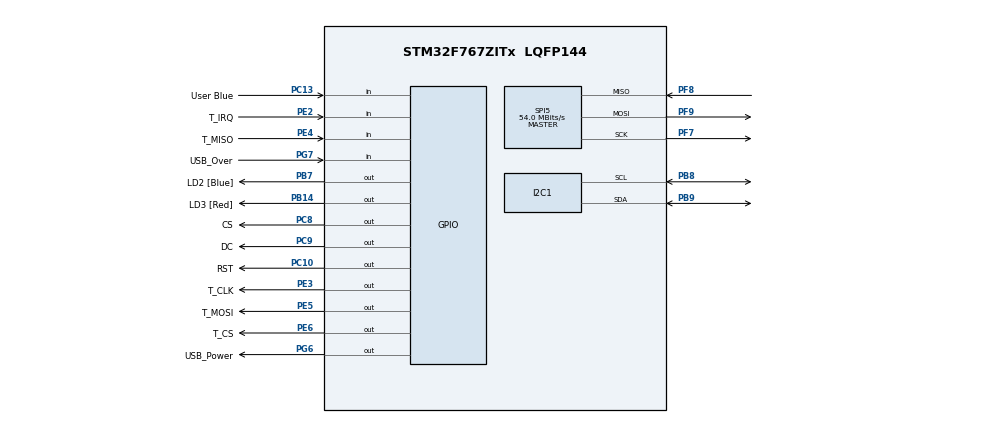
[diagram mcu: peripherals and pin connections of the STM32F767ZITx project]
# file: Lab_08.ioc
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CORTEX_M7.ART_ACCELERATOR_ENABLE=1
CORTEX_M7.CPU_DCache=Enabled
CORTEX_M7.CPU_ICache=Enabled
CORTEX_M7.MPU_Control=__NULL
CORTEX_M7.PREFETCH_ENABLE=1
I2C1.Timing=0x20404768
Mcu.Family=STM32F7
Mcu.Name=STM32F767ZITx
Mcu.Package=LQFP144
NVIC.PriorityGroup=NVIC_PRIORITYGROUP_4
PB14.GPIO_Label=LD3 [Red]
PB14.Signal=GPIO_Output
PB7.GPIO_Label=LD2 [Blue]
PB7.Signal=GPIO_Output
PB8.Mode=I2C
PB8.Signal=I2C1_SCL
PB9.Mode=I2C
PB9.Signal=I2C1_SDA
PC10.GPIO_Label=RST
PC10.GPIO_Speed=GPIO_SPEED_FREQ_VERY_HIGH
PC10.Signal=GPIO_Output
PC13.GPIO_Label=User Blue
PC13.Signal=GPIO_Input
PC8.GPIO_Label=CS
PC8.GPIO_Speed=GPIO_SPEED_FREQ_VERY_HIGH
PC8.Signal=GPIO_Output
PC9.GPIO_Label=DC
PC9.GPIO_Speed=GPIO_SPEED_FREQ_VERY_HIGH
PC9.Signal=GPIO_Output
PE2.GPIO_Label=T_IRQ
PE2.Signal=GPIO_Input
PE3.GPIO_Label=T_CLK
PE3.GPIO_Speed=GPIO_SPEED_FREQ_VERY_HIGH
PE3.Signal=GPIO_Output
PE4.GPIO_Label=T_MISO
PE4.Signal=GPIO_Input
PE5.GPIO_Label=T_MOSI
PE5.GPIO_Speed=GPIO_SPEED_FREQ_VERY_HIGH
PE5.Signal=GPIO_Output
PE6.GPIO_Label=T_CS
PE6.GPIO_Speed=GPIO_SPEED_FREQ_VERY_HIGH
PE6.Signal=GPIO_Output
PF7.Mode=Full_Duplex_Master
PF7.Signal=SPI5_SCK
PF8.Mode=Full_Duplex_Master
PF8.Signal=SPI5_MISO
PF9.Mode=Full_Duplex_Master
PF9.Signal=SPI5_MOSI
PG6.GPIO_Label=USB_Power
PG6.Signal=GPIO_Output
PG7.GPIO_Label=USB_Over
PG7.Signal=GPIO_Input
ProjectManager.HeapSize=0x200
ProjectManager.StackSize=0x400
ProjectManager.TargetToolchain=STM32CubeIDE
RCC.AHBFreq_Value=216000000
RCC.APB1CLKDivider=RCC_HCLK_DIV4
RCC.APB1Freq_Value=54000000
RCC.APB1TimFreq_Value=108000000
RCC.APB2CLKDivider=RCC_HCLK_DIV2
RCC.APB2Freq_Value=108000000
RCC.APB2TimFreq_Value=216000000
RCC.CortexFreq_Value=216000000
RCC.HCLKFreq_Value=216000000
RCC.HSE_VALUE=25000000
RCC.HSI_VALUE=16000000
RCC.LSE_VALUE=32768
RCC.PLLM=8
RCC.PLLN=216
RCC.PLLQ=9
RCC.SYSCLKFreq_VALUE=216000000
RCC.SYSCLKSource=RCC_SYSCLKSOURCE_PLLCLK
RCC.USBFreq_Value=48000000
RCC.VCOOutputFreq_Value=432000000
SPI5.CalculateBaudRate=54.0 MBits/s
SPI5.DataSize=SPI_DATASIZE_8BIT
SPI5.Direction=SPI_DIRECTION_2LINES
SPI5.Mode=SPI_MODE_MASTER
SPI5.NSSPMode=SPI_NSS_PULSE_DISABLE
SPI5.VirtualType=VM_MASTER
TIM1.ClockDivision=TIM_CLOCKDIVISION_DIV2
TIM1.Period=0
TIM1.Prescaler=10000
VP_RNG_VS_RNG.Mode=RNG_Activate
VP_TIM1_VS_ClockSourceINT.Mode=Internal
board=custom

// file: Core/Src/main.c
/* USER CODE BEGIN Header */
/**
  ******************************************************************************
  * @file           : main.c
  * @brief          : Main program body
  ******************************************************************************
  * @attention
  *
  * Copyright (c) 2023 STMicroelectronics.
  * All rights reserved.
  *
  * This software is licensed under terms that can be found in the LICENSE file
  * in the root directory of this software component.
  * If no LICENSE file comes with this software, it is provided AS-IS.
  *
  ******************************************************************************
  */
/* USER CODE END Header */
#include "main.h"
#include "i2c.h"
#include "rng.h"
#include "spi.h"
#include "tim.h"
#include "gpio.h"

/* USER CODE BEGIN Includes */

#include "ILI9341_GFX.h"
#include "ILI9341_STM32_Driver.h"
#include "ILI9341_Touchscreen.h"
#include "string.h"
#include "stdio.h"
#include "picture.h"
/* USER CODE END Includes */

/* USER CODE BEGIN PV */

u_int16_t rcolor ;
u_int16_t gcolor ;
u_int16_t bcolor ;
u_int16_t rgbcolor;

float h=30.0,t=40.0;
u_int8_t step =0;
HAL_StatusTypeDef status;

/* USER CODE END PV */

void SystemClock_Config(void);
/* USER CODE BEGIN PFP */

uint16_t CRC16_2(uint8_t *,uint8_t);
/* USER CODE END PFP */

int main(void)
{
  /* USER CODE BEGIN 1 */
  char str[50];
  uint8_t cmdBuffer[3];
  uint8_t dataBuffer[8];
  /* USER CODE END 1 */

  /* Enable I-Cache---------------------------------------------------------*/
  SCB_EnableICache();

  /* Enable D-Cache---------------------------------------------------------*/
  SCB_EnableDCache();

  /* MCU Configuration--------------------------------------------------------*/

  /* Reset of all peripherals, Initializes the Flash interface and the Systick. */
  HAL_Init();

  /* Configure the system clock */
  SystemClock_Config();

  /* Initialize all configured peripherals */
  MX_GPIO_Init();
  MX_RNG_Init();
  MX_SPI5_Init();
  MX_TIM1_Init();
  MX_I2C1_Init();
  /* USER CODE BEGIN 2 */
  ILI9341_Init();

  ILI9341_Set_Rotation(SCREEN_HORIZONTAL_2);

  ILI9341_Fill_Screen(WHITE);
  uint16_t red=0;
  uint16_t green=0;
  uint16_t blue=0;
  uint16_t timeout=0;
  cmdBuffer[0]=0x03;
  cmdBuffer[1]=0x00;
  cmdBuffer[2]=0x04;

  /* USER CODE END 2 */

  /* Infinite loop */
  /* USER CODE BEGIN WHILE */
  while (1)
  {
    /* USER CODE END WHILE
     * #define ILI9341_SCREEN_HEIGHT 240
		#define ILI9341_SCREEN_WIDTH 	320
     *  */

	  HAL_Delay(50);

	  HAL_I2C_Master_Transmit(&hi2c1, 0x5c<<1, cmdBuffer, 3, 200);
	  HAL_I2C_Master_Transmit(&hi2c1, 0x5c<<1, cmdBuffer, 3, 200);
	  HAL_Delay(1);
	  HAL_I2C_Master_Receive(&hi2c1, 0x5c<<1, dataBuffer, 8, 200);
	  uint16_t Rcrc = dataBuffer[7]<<8;
	  Rcrc +=dataBuffer[6];
	  if (Rcrc == CRC16_2(dataBuffer,6))
	  {
		  uint16_t temperature = ((dataBuffer[4]%0x7F)<<8)+dataBuffer[5];
		  t = temperature/10.0;
		  t=(((dataBuffer[4]&0x80)>>7)==1)?(t*(-1)):t;
		  uint16_t humidity=(dataBuffer[2]<<8)+dataBuffer[3];
		  h= humidity/10.0;

	  }
	  char temperature[4];
	  char Humudity[10];

	  sprintf(temperature,"%4.1fC",t);
	  ILI9341_Draw_Text(temperature, 20, 25, BLACK, 2, WHITE);

	  sprintf(Humudity,"%4.1f%%RH",h);
	  ILI9341_Draw_Text(Humudity, 180, 25, BLACK, 2, WHITE);

	  rcolor=((red*25+5)>>3)<<11;
	  gcolor=((green*25+5)>>2)<<5;
	  bcolor=(blue*25+5)>>3;
	  rgbcolor=rcolor|gcolor|bcolor;

	  if(TP_Touchpad_Pressed())
	  {
		  uint16_t x_pos=0;
		  uint16_t y_pos=0;
		  HAL_GPIO_WritePin(GPIOB, LD3_Pin|LD2_Pin, GPIO_PIN_SET);
		  uint16_t position_array[2];
		  if(TP_Read_Coordinates(position_array)==TOUCHPAD_DATA_OK)
		  {
			  x_pos= position_array[0];
			  y_pos=position_array[1];
			  if(x_pos>100 && x_pos<125&&y_pos>285&&y_pos<305)
			  {
				  red++;
			  	  if (red>10)
			  	  {

			  		  red=0;
			  	  }
			  }
			  if(x_pos>150 && x_pos<180&&y_pos>285&&y_pos<305)
			  {

				  green++;
			  	  if (green>10)
			  	  {
			  		green=0;
			  	  }
			  }
			  if(x_pos>200 && x_pos<230&&y_pos>285&&y_pos<305)
			  {

				  blue++;
				  if (blue>10)
				  {
					  blue=0;
				  }
			  }
			  if(x_pos>30 && x_pos<50&&y_pos>180&&y_pos<220)
			  {

			  	  ILI9341_Fill_Screen(WHITE);
			  	  ILI9341_Draw_Image((const char*)picture, SCREEN_HORIZONTAL_2);
			  	  ILI9341_Draw_Text("Group No18", 145, 45, rgbcolor, 2, WHITE);
			  	  ILI9341_Draw_Text("Jaruphat", 145, 65, rgbcolor, 2, WHITE);
			  	  ILI9341_Draw_Text("Khenprom", 145, 85, rgbcolor, 2, WHITE);
			  	  ILI9341_Draw_Text("64015019", 145, 105, rgbcolor, 2, WHITE);
			  	  ILI9341_Draw_Text("Pongphiphat", 135, 125, rgbcolor, 2, WHITE);
			  	  ILI9341_Draw_Text("Senta", 145, 145, rgbcolor, 2, WHITE);
			  	  ILI9341_Draw_Text("64015094", 145, 165, rgbcolor, 2, WHITE);
			  	  while(timeout<5000)
				  	  {
				  	  HAL_Delay(100);
				  	  timeout+=100;
				  	  if(TP_Touchpad_Pressed())
				  	  {
				  		 if(TP_Read_Coordinates(position_array)==TOUCHPAD_DATA_OK)
				  				  {
				  					  x_pos= position_array[0];
				  					  y_pos=position_array[1];
				  					  if(x_pos>70 && x_pos<190&&y_pos>180&&y_pos<300)
				  					  {
				  						  timeout=5000;
				  					  }
				  				  }

				  	  }

				  	  }
					timeout=0;
				  	ILI9341_Fill_Screen(WHITE);

			  }

		  }

		  char counter_buff[30];
//		  		sprintf(counter_buff,"POS X: %.3d", x_pos);
//		  		ILI9341_Draw_Text(counter_buff, 10, 80, BLACK, 2, WHITE);
//		  		sprintf(counter_buff,"POS Y: %.3d", y_pos);
//		  		ILI9341_Draw_Text(counter_buff, 10, 120, BLACK, 2, WHITE);

	  }
	  else
	  {
		  HAL_GPIO_WritePin(GPIOB, LD3_Pin|LD2_Pin, GPIO_PIN_RESET);

	  }
	  ILI9341_Draw_Filled_Circle(130,40, 30,rgbcolor);

	  char counter_buff[4];
	  ILI9341_Draw_Filled_Circle(30,110, 20, RED);
	  ILI9341_Draw_Filled_Rectangle_Coord(60, 95, 190, 125, 0xF5F5);
	  ILI9341_Draw_Filled_Rectangle_Coord(60, 95, (60+(red*13)), 125, RED);
	  sprintf(counter_buff, "    ");
	  ILI9341_Draw_Text(counter_buff, 200, 100, BLACK, 3, WHITE);

	  sprintf(counter_buff, "%d%%", red*10);
	  ILI9341_Draw_Text(counter_buff, 200, 100, BLACK, 3, WHITE);

	  ILI9341_Draw_Filled_Circle(30,160, 20, GREEN);
	  ILI9341_Draw_Filled_Rectangle_Coord(60, 145, 190, 175,0xB7B7);
	  ILI9341_Draw_Filled_Rectangle_Coord(60, 145, (60+(green*13)), 175,GREEN);
	  sprintf(counter_buff, "    ");
	  ILI9341_Draw_Text(counter_buff, 200, 150, BLACK, 3, WHITE);
	  sprintf(counter_buff, "%d%%", green*10);
	  ILI9341_Draw_Text(counter_buff, 200, 150, BLACK, 3, WHITE);

	  ILI9341_Draw_Filled_Circle(30,210, 20, BLUE);
	  ILI9341_Draw_Filled_Rectangle_Coord(60, 195, 190, 225,0x7E7E);
	  ILI9341_Draw_Filled_Rectangle_Coord(60, 195, (60+(blue*13)), 225,BLUE);
	  sprintf(counter_buff, "    ");
	  ILI9341_Draw_Text(counter_buff, 200, 200, BLACK, 3, WHITE);
	  sprintf(counter_buff, "%d%%", blue*10);
	  ILI9341_Draw_Text(counter_buff, 200, 200, BLACK, 3, WHITE);

  }
}

void SystemClock_Config(void)
{
  RCC_OscInitTypeDef RCC_OscInitStruct = {0};
  RCC_ClkInitTypeDef RCC_ClkInitStruct = {0};

  /** Configure the main internal regulator output voltage
  */
  __HAL_RCC_PWR_CLK_ENABLE();
  __HAL_PWR_VOLTAGESCALING_CONFIG(PWR_REGULATOR_VOLTAGE_SCALE1);

  /** Initializes the RCC Oscillators according to the specified parameters
  * in the RCC_OscInitTypeDef structure.
  */
  RCC_OscInitStruct.OscillatorType = RCC_OSCILLATORTYPE_HSI;
  RCC_OscInitStruct.HSIState = RCC_HSI_ON;
  RCC_OscInitStruct.HSICalibrationValue = RCC_HSICALIBRATION_DEFAULT;
  RCC_OscInitStruct.PLL.PLLState = RCC_PLL_ON;
  RCC_OscInitStruct.PLL.PLLSource = RCC_PLLSOURCE_HSI;
  RCC_OscInitStruct.PLL.PLLM = 8;
  RCC_OscInitStruct.PLL.PLLN = 200;
  RCC_OscInitStruct.PLL.PLLP = RCC_PLLP_DIV2;
  RCC_OscInitStruct.PLL.PLLQ = 9;
  RCC_OscInitStruct.PLL.PLLR = 2;
  if (HAL_RCC_OscConfig(&RCC_OscInitStruct) != HAL_OK)
  {
    Error_Handler();
  }

  /** Activate the Over-Drive mode
  */
  if (HAL_PWREx_EnableOverDrive() != HAL_OK)
  {
    Error_Handler();
  }

  /** Initializes the CPU, AHB and APB buses clocks
  */
  RCC_ClkInitStruct.ClockType = RCC_CLOCKTYPE_HCLK|RCC_CLOCKTYPE_SYSCLK
                              |RCC_CLOCKTYPE_PCLK1|RCC_CLOCKTYPE_PCLK2;
  RCC_ClkInitStruct.SYSCLKSource = RCC_SYSCLKSOURCE_PLLCLK;
  RCC_ClkInitStruct.AHBCLKDivider = RCC_SYSCLK_DIV1;
  RCC_ClkInitStruct.APB1CLKDivider = RCC_HCLK_DIV4;
  RCC_ClkInitStruct.APB2CLKDivider = RCC_HCLK_DIV2;

  if (HAL_RCC_ClockConfig(&RCC_ClkInitStruct, FLASH_LATENCY_6) != HAL_OK)
  {
    Error_Handler();
  }
}

/* USER CODE BEGIN 4 */
uint16_t CRC16_2 (uint8_t *ptr, uint8_t length)
{
       uint16_t crc = 0xFFFF;
       uint8_t s = 0x00;
       while (length--)
       {
         crc ^= *ptr++;
         for (s =0 ;s< 8; s++)
         {
           if ((crc & 0x01) != 0)
           {
             crc >>= 1;
             crc ^= 0xA001;
           }
           else crc >>= 1;
         }

       }
       return crc;
}

/* USER CODE END 4 */

void Error_Handler(void)
{
  __disable_irq();
  while (1)
  {
  }
}
